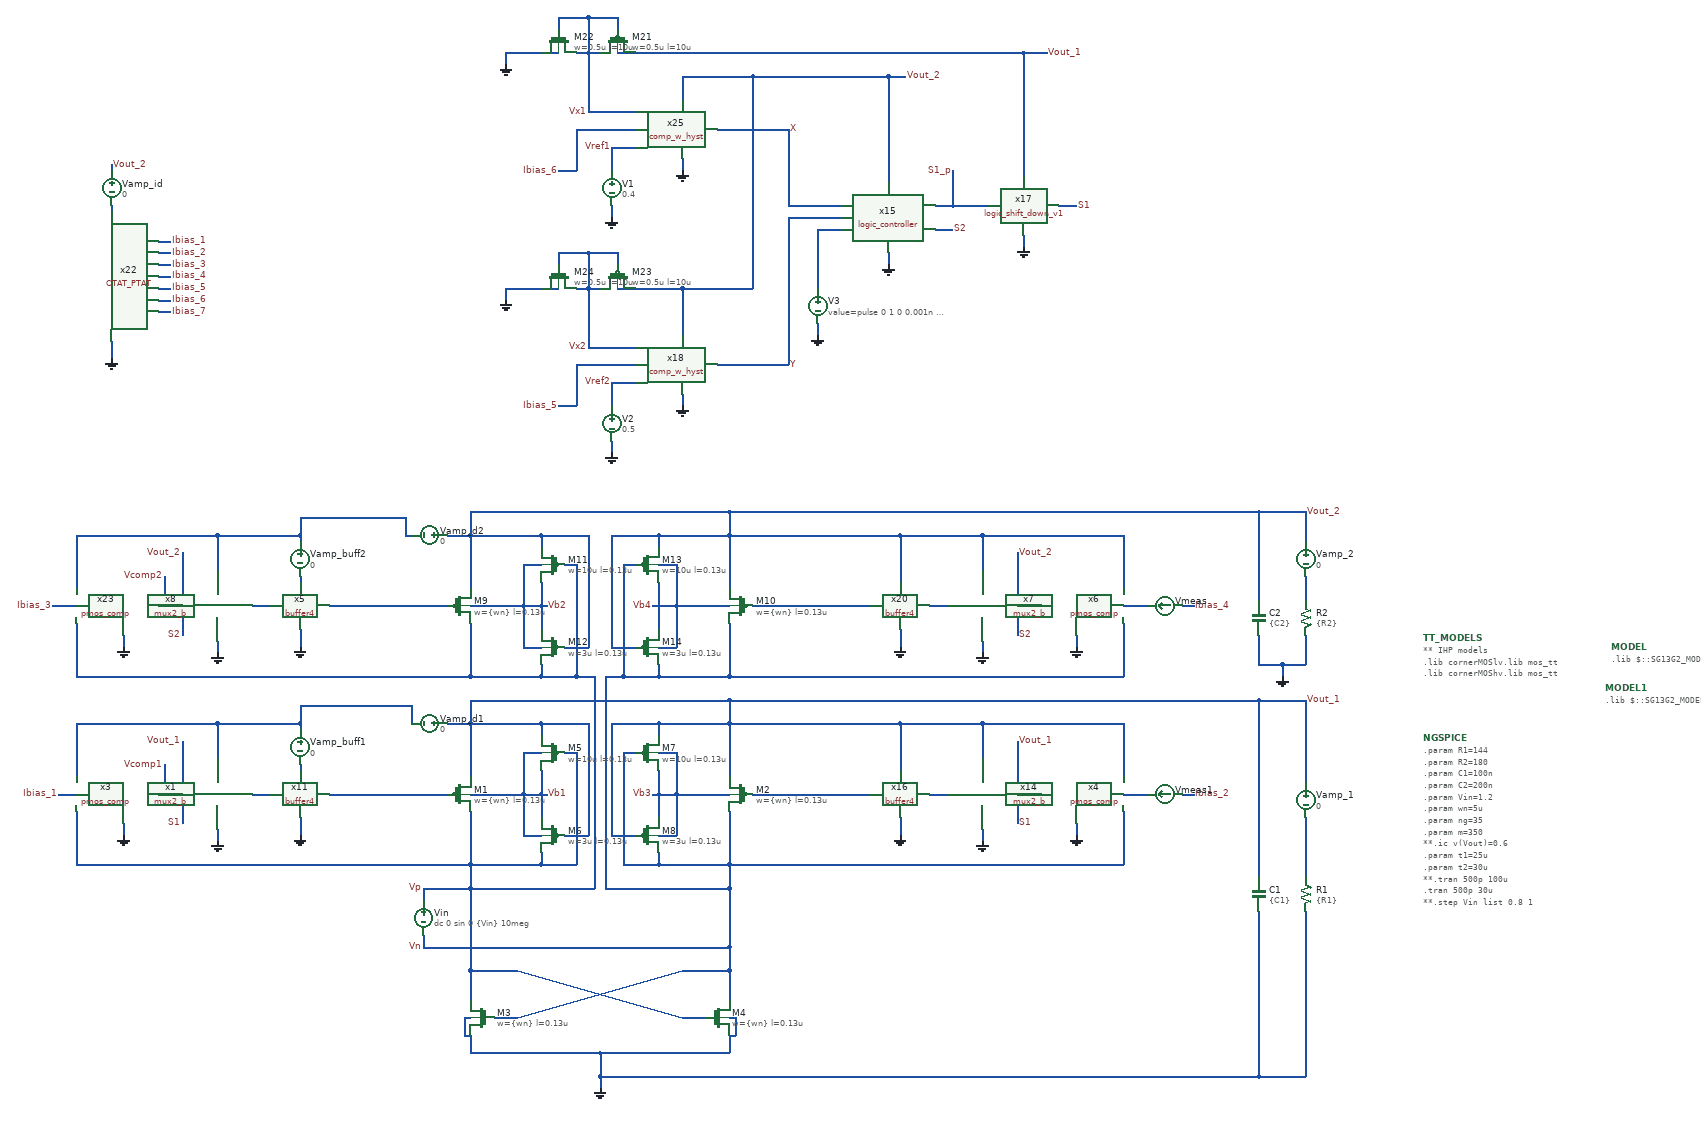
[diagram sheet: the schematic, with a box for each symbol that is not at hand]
v {xschem version=3.4.6 file_version=1.2}
G {}
K {}
V {}
S {}
E {}
P 4 1 1950 -490 {}
N 910 -700 930 -700 {lab=Vp}
N 910 -560 950 -560 {lab=Vout_1}
N 1010 -700 1030 -700 {lab=Vn}
N 990 -560 1030 -560 {lab=Vout_1}
N 1070 -630 1070 -590 {lab=Vb3}
N 1070 -670 1070 -630 {lab=Vb3}
N 870 -630 870 -590 {lab=Vb1}
N 840 -630 870 -630 {lab=Vb1}
N 870 -670 870 -630 {lab=Vb1}
N 930 -700 930 -510 {lab=Vp}
N 870 -510 930 -510 {lab=Vp}
N 750 -600 750 -510 {lab=Vp}
N 1190 -600 1190 -510 {lab=Vn}
N 1010 -700 1010 -510 {lab=Vn}
N 1070 -510 1190 -510 {lab=Vn}
N 990 -750 990 -560 {lab=Vout_1}
N 1070 -750 1190 -750 {lab=Vout_1}
N 950 -750 950 -560 {lab=Vout_1}
N 970 -190 1190 -190 {lab=GND}
N 1190 -330 1190 -280 {lab=Vn}
N 750 -330 750 -280 {lab=Vp}
N 790 -250 830 -250 {lab=Vn}
N 1110 -250 1150 -250 {lab=Vp}
N 830 -250 1110 -330 {lab=Vn}
N 830 -330 1110 -250 {lab=Vp}
N 750 -330 830 -330 {lab=Vp}
N 750 -470 750 -330 {lab=Vp}
N 1110 -330 1190 -330 {lab=Vn}
N 1190 -370 1190 -330 {lab=Vn}
N 670 -390 670 -370 {lab=Vn}
N 670 -370 1190 -370 {lab=Vn}
N 1190 -470 1190 -370 {lab=Vn}
N 670 -470 670 -450 {lab=Vp}
N 670 -470 750 -470 {lab=Vp}
N 750 -510 750 -470 {lab=Vp}
N 840 -700 870 -700 {lab=Vb1}
N 840 -700 840 -630 {lab=Vb1}
N 840 -560 870 -560 {lab=Vb1}
N 840 -630 840 -560 {lab=Vb1}
N 1070 -700 1100 -700 {lab=Vb3}
N 1100 -700 1100 -630 {lab=Vb3}
N 1070 -630 1100 -630 {lab=Vb3}
N 1070 -560 1100 -560 {lab=Vb3}
N 1100 -630 1100 -560 {lab=Vb3}
N 80 -600 80 -510 {lab=Vp}
N 80 -750 80 -660 {lab=#net1}
N 750 -790 750 -750 {lab=Vout_1}
N 750 -790 1190 -790 {lab=Vout_1}
N 1190 -790 1190 -750 {lab=Vout_1}
N 970 -150 970 -130 {lab=GND}
N 750 -190 970 -190 {lab=GND}
N 2090 -430 2090 -150 {lab=GND}
N 2170 -430 2170 -150 {lab=GND}
N 2090 -150 2170 -150 {lab=GND}
N 2090 -790 2090 -490 {lab=Vout_1}
N 2170 -590 2170 -490 {lab=#net2}
N 2170 -790 2170 -650 {lab=Vout_1}
N 1190 -250 1200 -250 {lab=GND}
N 1200 -250 1200 -220 {lab=GND}
N 1190 -220 1200 -220 {lab=GND}
N 1190 -220 1190 -190 {lab=GND}
N 750 -220 750 -190 {lab=GND}
N 740 -250 750 -250 {lab=GND}
N 740 -250 740 -220 {lab=GND}
N 740 -220 750 -220 {lab=GND}
N 510 -630 710 -630 {lab=#net3}
N 230 -680 230 -630 {lab=Vcomp1}
N 220 -630 230 -630 {lab=Vcomp1}
N 870 -630 880 -630 {lab=Vb1}
N 460 -590 460 -560 {lab=GND}
N 160 -580 160 -560 {lab=GND}
N 1860 -600 1860 -510 {lab=Vn}
N 1860 -750 1860 -660 {lab=Vout_1}
N 1480 -750 1480 -670 {lab=Vout_1}
N 1480 -590 1480 -560 {lab=GND}
N 1780 -580 1780 -560 {lab=GND}
N 1190 -510 1860 -510 {lab=Vn}
N 1190 -750 1480 -750 {lab=Vout_1}
N 1230 -630 1430 -630 {lab=#net4}
N 910 -1020 930 -1020 {lab=Vp}
N 910 -880 950 -880 {lab=Vout_2}
N 1010 -1020 1030 -1020 {lab=Vn}
N 990 -880 1030 -880 {lab=Vout_2}
N 1070 -950 1070 -910 {lab=Vb4}
N 1070 -990 1070 -950 {lab=Vb4}
N 870 -950 870 -910 {lab=Vb2}
N 840 -950 870 -950 {lab=Vb2}
N 870 -990 870 -950 {lab=Vb2}
N 870 -1070 950 -1070 {lab=Vout_2}
N 930 -1020 930 -830 {lab=Vp}
N 870 -830 930 -830 {lab=Vp}
N 750 -920 750 -830 {lab=Vp}
N 1190 -920 1190 -830 {lab=Vn}
N 1010 -1020 1010 -830 {lab=Vn}
N 1070 -830 1190 -830 {lab=Vn}
N 990 -1070 990 -880 {lab=Vout_2}
N 1070 -1070 1190 -1070 {lab=Vout_2}
N 950 -1070 950 -880 {lab=Vout_2}
N 840 -1020 870 -1020 {lab=Vb2}
N 840 -1020 840 -950 {lab=Vb2}
N 840 -880 870 -880 {lab=Vb2}
N 840 -950 840 -880 {lab=Vb2}
N 1070 -1020 1100 -1020 {lab=Vb4}
N 1100 -1020 1100 -950 {lab=Vb4}
N 1070 -950 1100 -950 {lab=Vb4}
N 1070 -880 1100 -880 {lab=Vb4}
N 1100 -950 1100 -880 {lab=Vb4}
N 80 -920 80 -830 {lab=Vp}
N 80 -1070 80 -980 {lab=#net5}
N 510 -950 710 -950 {lab=#net6}
N 230 -1000 230 -950 {lab=Vcomp2}
N 220 -950 230 -950 {lab=Vcomp2}
N 870 -950 880 -950 {lab=Vb2}
N 460 -910 460 -880 {lab=GND}
N 160 -900 160 -880 {lab=GND}
N 1860 -920 1860 -830 {lab=Vn}
N 1860 -1070 1860 -980 {lab=Vout_2}
N 1480 -1070 1480 -990 {lab=Vout_2}
N 1480 -910 1480 -880 {lab=GND}
N 1780 -900 1780 -880 {lab=GND}
N 1190 -830 1860 -830 {lab=Vn}
N 1190 -1070 1480 -1070 {lab=Vout_2}
N 1230 -950 1430 -950 {lab=#net7}
N 750 -470 960 -470 {lab=Vp}
N 930 -830 960 -830 {lab=Vp}
N 960 -830 960 -470 {lab=Vp}
N 980 -830 1010 -830 {lab=Vn}
N 980 -830 980 -470 {lab=Vn}
N 980 -470 1190 -470 {lab=Vn}
N 1190 -510 1190 -470 {lab=Vn}
N 2130 -850 2170 -850 {lab=GND}
N 2130 -850 2130 -830 {lab=GND}
N 2090 -850 2130 -850 {lab=GND}
N 970 -190 970 -150 {lab=GND}
N 2170 -900 2170 -850 {lab=GND}
N 2090 -900 2090 -850 {lab=GND}
N 2090 -1110 2090 -960 {lab=Vout_2}
N 2170 -1000 2170 -960 {lab=#net8}
N 2170 -1110 2170 -1060 {lab=Vout_2}
N 750 -1110 750 -1070 {lab=Vout_2}
N 1190 -1110 2090 -1110 {lab=Vout_2}
N 1190 -1110 1190 -1070 {lab=Vout_2}
N 750 -1110 1190 -1110 {lab=Vout_2}
N 50 -630 80 -630 {lab=Ibias_1}
N 1190 -790 2090 -790 {lab=Vout_1}
N 2090 -790 2170 -790 {lab=Vout_1}
N 2090 -1110 2170 -1110 {lab=Vout_2}
N 80 -510 750 -510 {lab=Vp}
N 1620 -1070 1860 -1070 {lab=Vout_2}
N 1620 -750 1860 -750 {lab=Vout_1}
N 80 -830 750 -830 {lab=Vp}
N 970 -150 2090 -150 {lab=GND}
N 230 -950 260 -950 {lab=Vcomp2}
N 230 -630 260 -630 {lab=Vcomp1}
N 140 -1400 140 -1370 {lab=GND}
N 1000 -1950 1000 -1930 {lab=Vx1}
N 900 -1950 950 -1950 {lab=Vx1}
N 900 -1950 900 -1930 {lab=Vx1}
N 930 -1890 950 -1890 {lab=Vx1}
N 950 -1950 950 -1890 {lab=Vx1}
N 950 -1950 1000 -1950 {lab=Vx1}
N 950 -1890 970 -1890 {lab=Vx1}
N 950 -1790 1030 -1790 {lab=Vx1}
N 950 -1890 950 -1790 {lab=Vx1}
N 990 -1730 990 -1690 {lab=Vref1}
N 990 -1730 1030 -1730 {lab=Vref1}
N 930 -1760 930 -1690 {lab=Ibias_6}
N 930 -1760 1030 -1760 {lab=Ibias_6}
N 990 -1630 990 -1610 {lab=GND}
N 810 -1890 810 -1870 {lab=GND}
N 810 -1890 900 -1890 {lab=GND}
N 1110 -1710 1110 -1690 {lab=GND}
N 1000 -1550 1000 -1530 {lab=Vx2}
N 900 -1550 950 -1550 {lab=Vx2}
N 900 -1550 900 -1530 {lab=Vx2}
N 930 -1490 950 -1490 {lab=Vx2}
N 950 -1550 950 -1490 {lab=Vx2}
N 950 -1550 1000 -1550 {lab=Vx2}
N 950 -1490 970 -1490 {lab=Vx2}
N 950 -1390 1030 -1390 {lab=Vx2}
N 950 -1490 950 -1390 {lab=Vx2}
N 990 -1330 990 -1290 {lab=Vref2}
N 990 -1330 1030 -1330 {lab=Vref2}
N 930 -1360 930 -1290 {lab=Ibias_5}
N 930 -1360 1030 -1360 {lab=Ibias_5}
N 990 -1230 990 -1210 {lab=GND}
N 810 -1490 810 -1470 {lab=GND}
N 810 -1490 900 -1490 {lab=GND}
N 1110 -1310 1110 -1290 {lab=GND}
N 1110 -1850 1110 -1810 {lab=Vout_2}
N 1460 -1550 1460 -1530 {lab=GND}
N 1290 -1630 1380 -1630 {lab=X}
N 1170 -1360 1290 -1360 {lab=Y}
N 1230 -1850 1230 -1490 {lab=Vout_2}
N 1170 -1760 1290 -1760 {lab=X}
N 1290 -1760 1290 -1630 {lab=X}
N 1290 -1610 1290 -1360 {lab=Y}
N 1290 -1610 1380 -1610 {lab=Y}
N 1460 -1850 1490 -1850 {lab=Vout_2}
N 1540 -1590 1570 -1590 {lab=S2}
N 1570 -1630 1630 -1630 {lab=S1_p}
N 1690 -1890 1690 -1680 {lab=Vout_1}
N 1690 -1890 1730 -1890 {lab=Vout_1}
N 1690 -1580 1690 -1560 {lab=GND}
N 1750 -1630 1780 -1630 {lab=S1}
N 380 -630 410 -630 {lab=#net9}
N 320 -570 320 -550 {lab=GND}
N 320 -750 320 -690 {lab=#net1}
N 80 -750 320 -750 {lab=#net1}
N 260 -610 260 -580 {lab=S1}
N 260 -720 260 -650 {lab=Vout_1}
N 1680 -630 1720 -630 {lab=#net10}
N 1530 -630 1560 -630 {lab=#net11}
N 1620 -570 1620 -550 {lab=GND}
N 1620 -750 1620 -690 {lab=Vout_1}
N 1680 -610 1680 -580 {lab=S1}
N 1680 -720 1680 -650 {lab=Vout_1}
N 1480 -750 1620 -750 {lab=Vout_1}
N 380 -950 410 -950 {lab=#net12}
N 320 -890 320 -870 {lab=GND}
N 320 -1070 320 -1010 {lab=#net5}
N 260 -930 260 -900 {lab=S2}
N 260 -1040 260 -970 {lab=Vout_2}
N 80 -1070 320 -1070 {lab=#net5}
N 1680 -950 1720 -950 {lab=#net13}
N 1530 -950 1560 -950 {lab=#net14}
N 1620 -890 1620 -870 {lab=GND}
N 1620 -1070 1620 -1010 {lab=Vout_2}
N 1680 -930 1680 -900 {lab=S2}
N 1680 -1040 1680 -970 {lab=Vout_2}
N 1480 -1070 1620 -1070 {lab=Vout_2}
N 1110 -1490 1230 -1490 {lab=Vout_2}
N 1000 -1890 1690 -1890 {lab=Vout_1}
N 1570 -1690 1570 -1630 {lab=S1_p}
N 1540 -1630 1570 -1630 {lab=S1_p}
N 1340 -1590 1380 -1590 {lab=#net15}
N 1860 -630 1900 -630 {lab=#net16}
N 1860 -950 1900 -950 {lab=#net17}
N 40 -950 80 -950 {lab=Ibias_3}
N 220 -1570 240 -1570 {lab=Ibias_1}
N 220 -1550 240 -1550 {lab=Ibias_2}
N 220 -1530 240 -1530 {lab=Ibias_3}
N 220 -1510 240 -1510 {lab=Ibias_4}
N 220 -1490 240 -1490 {lab=Ibias_5}
N 220 -1470 240 -1470 {lab=Ibias_6}
N 220 -1450 240 -1450 {lab=Ibias_7}
N 900 -1290 930 -1290 {lab=Ibias_5}
N 900 -1690 930 -1690 {lab=Ibias_6}
N 710 -1070 750 -1070 {lab=Vout_2}
N 710 -750 750 -750 {lab=Vout_1}
N 460 -1070 460 -1060 {lab=#net5}
N 320 -1070 460 -1070 {lab=#net5}
N 460 -1000 460 -990 {lab=#net18}
N 460 -680 460 -670 {lab=#net19}
N 460 -750 460 -740 {lab=#net1}
N 320 -750 460 -750 {lab=#net1}
N 640 -1070 650 -1070 {lab=#net5}
N 640 -1100 640 -1070 {lab=#net5}
N 460 -1100 460 -1070 {lab=#net5}
N 460 -1100 640 -1100 {lab=#net5}
N 650 -780 650 -750 {lab=#net1}
N 460 -780 460 -750 {lab=#net1}
N 460 -780 650 -780 {lab=#net1}
N 140 -1630 140 -1620 {lab=#net20}
N 140 -1700 140 -1690 {lab=Vout_2}
N 1960 -950 1980 -950 {lab=Ibias_4}
N 1960 -630 1980 -630 {lab=Ibias_2}
N 1060 -950 1070 -950 {lab=Vb4}
N 1060 -630 1070 -630 {lab=Vb3}
N 1110 -1490 1110 -1410 {lab=Vout_2}
N 1000 -1490 1110 -1490 {lab=Vout_2}
N 1110 -1850 1230 -1850 {lab=Vout_2}
N 1460 -1850 1460 -1670 {lab=Vout_2}
N 1230 -1850 1460 -1850 {lab=Vout_2}
N 870 -750 950 -750 {lab=Vout_1}
N 870 -1070 870 -1050 {lab=Vout_2}
N 750 -1070 870 -1070 {lab=Vout_2}
N 1070 -1070 1070 -1050 {lab=Vout_2}
N 990 -1070 1070 -1070 {lab=Vout_2}
N 870 -850 870 -830 {lab=Vp}
N 750 -830 870 -830 {lab=Vp}
N 750 -1070 750 -980 {lab=Vout_2}
N 750 -950 840 -950 {lab=Vb2}
N 1190 -1070 1190 -980 {lab=Vout_2}
N 1100 -950 1190 -950 {lab=Vb4}
N 1190 -750 1190 -660 {lab=Vout_1}
N 1100 -630 1190 -630 {lab=Vb3}
N 750 -750 750 -660 {lab=Vout_1}
N 750 -630 840 -630 {lab=Vb1}
N 870 -750 870 -730 {lab=Vout_1}
N 750 -750 870 -750 {lab=Vout_1}
N 1070 -750 1070 -730 {lab=Vout_1}
N 990 -750 1070 -750 {lab=Vout_1}
N 870 -530 870 -510 {lab=Vp}
N 750 -510 870 -510 {lab=Vp}
N 1070 -530 1070 -510 {lab=Vn}
N 1010 -510 1070 -510 {lab=Vn}
N 1070 -850 1070 -830 {lab=Vn}
N 1010 -830 1070 -830 {lab=Vn}
N 1340 -1430 1340 -1410 {lab=GND}
N 1340 -1590 1340 -1490 {lab=#net15}
C {sg13g2_pr/sg13_lv_pmos.sym} 730 -630 0 0 {name=M1
l=0.13u
w=\{wn\}
ng=\{ng\}
m=\{5*m\}
model=sg13_lv_pmos
spiceprefix=X
}
C {sg13g2_pr/sg13_lv_pmos.sym} 1210 -630 0 1 {name=M2
l=0.13u
w=\{wn\}
ng=\{ng\}
m=\{5*m\}
model=sg13_lv_pmos
spiceprefix=X
}
C {sg13g2_pr/sg13_lv_nmos.sym} 770 -250 0 1 {name=M3
l=0.13u
w=\{wn\}
ng=\{ng\}
m=\{3*m\}
model=sg13_lv_nmos
spiceprefix=X
}
C {sg13g2_pr/sg13_lv_nmos.sym} 1170 -250 0 0 {name=M4
l=0.13u
w=\{wn\}
ng=\{ng\}
m=\{3*m\}
model=sg13_lv_nmos
spiceprefix=X
}
C {sg13g2_pr/sg13_lv_pmos.sym} 890 -700 0 1 {name=M5
l=0.13u
w=10u
ng=1
m=1
model=sg13_lv_pmos
spiceprefix=X
}
C {sg13g2_pr/sg13_lv_pmos.sym} 890 -560 2 0 {name=M6
l=0.13u
w=3u
ng=1
m=1
model=sg13_lv_pmos
spiceprefix=X
}
C {sg13g2_pr/sg13_lv_pmos.sym} 1050 -700 0 0 {name=M7
l=0.13u
w=10u
ng=1
m=1
model=sg13_lv_pmos
spiceprefix=X
}
C {sg13g2_pr/sg13_lv_pmos.sym} 1050 -560 2 1 {name=M8
l=0.13u
w=3u
ng=1
m=1
model=sg13_lv_pmos
spiceprefix=X
}
C {vsource.sym} 670 -420 0 1 {name=Vin value="dc 0 sin 0 \{Vin\} 10meg" savecurrent=false}
C {lab_pin.sym} 670 -470 0 0 {name=p1 sig_type=std_logic lab=Vp}
C {lab_pin.sym} 670 -370 0 0 {name=p2 sig_type=std_logic lab=Vn}
C {gnd.sym} 140 -1370 0 0 {name=l1 lab=GND}
C {capa.sym} 2090 -460 0 0 {name=C1
m=1
value=\{C1\}
footprint=1206
device="ceramic capacitor"}
C {res.sym} 2170 -460 0 0 {name=R1
value=\{R1\}
footprint=1206
device=resistor
m=1}
C {vsource.sym} 2170 -620 0 0 {name=Vamp_1 value=0 savecurrent=false}
C {lab_pin.sym} 2170 -790 0 1 {name=p3 sig_type=std_logic lab=Vout_1}
C {gnd.sym} 970 -130 0 0 {name=l3 lab=GND}
C {lab_pin.sym} 230 -680 0 0 {name=p4 sig_type=std_logic lab=Vcomp1}
C {lab_pin.sym} 880 -630 0 1 {name=p6 sig_type=std_logic lab=Vb1}
C {gnd.sym} 160 -560 0 0 {name=l4 lab=GND}
C {gnd.sym} 460 -560 0 0 {name=l5 lab=GND}
C {code_shown.sym} 2370 -895 0 0 {
name=TT_MODELS
only_toplevel=true
value="
** IHP models
.lib cornerMOSlv.lib mos_tt
.lib cornerMOShv.lib mos_tt
"
spice_ignore=false
      }
C {code_shown.sym} 2370 -725 0 0 {name=NGSPICE
only_toplevel=false
value="
.param R1=144
.param R2=180
.param C1=100n
.param C2=200n
.param Vin=1.2
.param wn=5u
.param ng=35
.param m=350
**.ic v(Vout)=0.6
.param t1=25u
.param t2=30u
**.tran 500p 100u
.tran 500p 30u
**.step Vin list 0.8 1
.meas tran i_r1 AVG i(Vamp_1) from=t1 to=t2
.meas tran v_reg_1 AVG v(vout_1) from=t1 to=t2
.meas tran v_reg_2 AVG v(vout_2) from=t1 to=t2
.meas tran p_out_1 AVG par('((v(Vout_1)**2)/R1)') from=t1 to=t2
.meas tran p_out_2 AVG par('((v(Vout_2)**2)/R2)') from=t1 to=t2
.meas tran p_out AVG par('((v(Vout_1)**2)/R1)+((v(Vout_2)**2)/R2)') from=t1 to=t2
.meas tran p_in AVG par('-(v(Vp)-v(Vn))*i(Vin)') from=t1 to=t2
*.meas tran p_d1 AVG par('v(Vout_1)*(i(Vamp_gate1)+i(Vamp_buff1))*2') from=t1 to=t2
*.meas tran p_d2 AVG par('v(Vout_2)*(i(Vamp_gate2)+i(Vamp_buff2))*2') from=t1 to=t2
.meas tran p_id AVG par('v(Vout_2)*i(Vamp_id)') from=t1 to=t2
*.meas tran p_active_diodes param='(p_d1+p_d2)/p_in*100'
.meas tran p_id_percent param='p_id/p_in*100'
.meas tran i_driver1 AVG par('i(Vamp_d1)') from=t1 to=t2
.meas tran i_driver2 AVG par('i(Vamp_d2)') from=t1 to=t2
.meas tran PCE param='p_out/p_in' from=t1 to=t2
.meas tran VCR_1 param='v_reg_1/Vin'
.meas tran VCR_2 param='v_reg_2/Vin'
.save all
"}
C {gnd.sym} 1780 -560 0 1 {name=l6 lab=GND}
C {gnd.sym} 1480 -560 0 1 {name=l7 lab=GND}
C {sg13g2_pr/sg13_lv_pmos.sym} 730 -950 0 0 {name=M9
l=0.13u
w=\{wn\}
ng=\{ng\}
m=\{5*m\}
model=sg13_lv_pmos
spiceprefix=X
}
C {sg13g2_pr/sg13_lv_pmos.sym} 1210 -950 0 1 {name=M10
l=0.13u
w=\{wn\}
ng=\{ng\}
m=\{5*m\}
model=sg13_lv_pmos
spiceprefix=X
}
C {sg13g2_pr/sg13_lv_pmos.sym} 890 -1020 0 1 {name=M11
l=0.13u
w=10u
ng=1
m=1
model=sg13_lv_pmos
spiceprefix=X
}
C {sg13g2_pr/sg13_lv_pmos.sym} 890 -880 2 0 {name=M12
l=0.13u
w=3u
ng=1
m=1
model=sg13_lv_pmos
spiceprefix=X
}
C {sg13g2_pr/sg13_lv_pmos.sym} 1050 -1020 0 0 {name=M13
l=0.13u
w=10u
ng=1
m=1
model=sg13_lv_pmos
spiceprefix=X
}
C {sg13g2_pr/sg13_lv_pmos.sym} 1050 -880 2 1 {name=M14
l=0.13u
w=3u
ng=1
m=1
model=sg13_lv_pmos
spiceprefix=X
}
C {lab_pin.sym} 230 -1000 0 0 {name=p11 sig_type=std_logic lab=Vcomp2}
C {lab_pin.sym} 880 -950 0 1 {name=p14 sig_type=std_logic lab=Vb2}
C {gnd.sym} 160 -880 0 0 {name=l11 lab=GND}
C {gnd.sym} 460 -880 0 0 {name=l12 lab=GND}
C {gnd.sym} 1780 -880 0 1 {name=l14 lab=GND}
C {gnd.sym} 1480 -880 0 1 {name=l15 lab=GND}
C {capa.sym} 2090 -930 0 0 {name=C2
m=1
value=\{C2\}
footprint=1206
device="ceramic capacitor"}
C {res.sym} 2170 -930 0 0 {name=R2
value=\{R2\}
footprint=1206
device=resistor
m=1}
C {vsource.sym} 2170 -1030 0 0 {name=Vamp_2 value=0 savecurrent=false}
C {gnd.sym} 2130 -830 0 1 {name=l18 lab=GND}
C {lab_pin.sym} 2170 -1110 0 1 {name=p20 sig_type=std_logic lab=Vout_2}
C {sg13g2_pr/sg13_lv_pmos.sym} 1000 -1910 1 0 {name=M21
l=10u
w=0.5u
ng=1
m=19
model=sg13_lv_pmos
spiceprefix=X
}
C {sg13g2_pr/sg13_lv_nmos.sym} 900 -1910 1 0 {name=M22
l=10u
w=0.5u
ng=1
m=1
model=sg13_lv_nmos
spiceprefix=X
}
C {gnd.sym} 810 -1870 0 0 {name=l22 lab=GND}
C {vsource.sym} 990 -1660 0 0 {name=V1 value=0.4 savecurrent=false}
C {gnd.sym} 990 -1610 0 0 {name=l24 lab=GND}
C {gnd.sym} 1110 -1690 0 0 {name=l25 lab=GND}
C {sg13g2_pr/sg13_lv_pmos.sym} 1000 -1510 1 0 {name=M23
l=10u
w=0.5u
ng=1
m=10
model=sg13_lv_pmos
spiceprefix=X
}
C {sg13g2_pr/sg13_lv_nmos.sym} 900 -1510 1 0 {name=M24
l=10u
w=0.5u
ng=1
m=1
model=sg13_lv_nmos
spiceprefix=X
}
C {gnd.sym} 810 -1470 0 0 {name=l26 lab=GND}
C {vsource.sym} 990 -1260 0 0 {name=V2 value=0.5 savecurrent=false}
C {lab_pin.sym} 1730 -1890 0 1 {name=p27 sig_type=std_logic lab=Vout_1}
C {lab_pin.sym} 1490 -1850 0 1 {name=p28 sig_type=std_logic lab=Vout_2}
C {gnd.sym} 1460 -1530 0 0 {name=l30 lab=GND}
C {lab_pin.sym} 1570 -1590 0 1 {name=p26 sig_type=std_logic lab=S2}
C {gnd.sym} 1690 -1560 0 0 {name=l32 lab=GND}
C {lab_pin.sym} 1780 -1630 0 1 {name=p29 sig_type=std_logic lab=S1}
C {gnd.sym} 320 -550 0 0 {name=l33 lab=GND}
C {lab_pin.sym} 260 -720 0 0 {name=p30 sig_type=std_logic lab=Vout_1}
C {lab_pin.sym} 260 -580 0 0 {name=p31 sig_type=std_logic lab=S1}
C {gnd.sym} 1620 -550 0 1 {name=l34 lab=GND}
C {lab_pin.sym} 1680 -720 0 1 {name=p32 sig_type=std_logic lab=Vout_1}
C {lab_pin.sym} 1680 -580 0 1 {name=p33 sig_type=std_logic lab=S1}
C {gnd.sym} 320 -870 0 0 {name=l35 lab=GND}
C {lab_pin.sym} 260 -1040 0 0 {name=p34 sig_type=std_logic lab=Vout_2}
C {lab_pin.sym} 260 -900 0 0 {name=p35 sig_type=std_logic lab=S2}
C {gnd.sym} 1620 -870 0 1 {name=l36 lab=GND}
C {lab_pin.sym} 1680 -1040 0 1 {name=p36 sig_type=std_logic lab=Vout_2}
C {lab_pin.sym} 1680 -900 0 1 {name=p37 sig_type=std_logic lab=S2}
C {lab_pin.sym} 950 -1790 0 0 {name=p38 sig_type=std_logic lab=Vx1}
C {lab_pin.sym} 950 -1390 0 0 {name=p39 sig_type=std_logic lab=Vx2}
C {lab_pin.sym} 1290 -1360 0 1 {name=p41 sig_type=std_logic lab=Y}
C {lab_pin.sym} 1290 -1760 0 1 {name=p42 sig_type=std_logic lab=X}
C {lab_pin.sym} 990 -1730 0 0 {name=p43 sig_type=std_logic lab=Vref1}
C {lab_pin.sym} 990 -1330 0 0 {name=p44 sig_type=std_logic lab=Vref2}
C {lab_pin.sym} 1570 -1690 0 0 {name=p45 sig_type=std_logic lab=S1_p}
C {gnd.sym} 990 -1210 0 0 {name=l27 lab=GND}
C {gnd.sym} 1110 -1290 0 0 {name=l38 lab=GND}
C {lab_pin.sym} 140 -1700 0 1 {name=p49 sig_type=std_logic lab=Vout_2}
C {lab_pin.sym} 240 -1530 0 1 {name=p52 sig_type=std_logic lab=Ibias_3}
C {lab_pin.sym} 240 -1490 0 1 {name=p54 sig_type=std_logic lab=Ibias_5}
C {lab_pin.sym} 240 -1470 0 1 {name=p55 sig_type=std_logic lab=Ibias_6}
C {lab_pin.sym} 240 -1450 0 1 {name=p56 sig_type=std_logic lab=Ibias_7}
C {lab_pin.sym} 50 -630 0 0 {name=p57 sig_type=std_logic lab=Ibias_1}
C {lab_pin.sym} 1980 -630 0 1 {name=p58 sig_type=std_logic lab=Ibias_2}
C {lab_pin.sym} 1980 -950 0 1 {name=p59 sig_type=std_logic lab=Ibias_4}
C {lab_pin.sym} 40 -950 0 0 {name=p60 sig_type=std_logic lab=Ibias_3}
C {lab_pin.sym} 900 -1290 0 0 {name=p61 sig_type=std_logic lab=Ibias_5}
C {lab_pin.sym} 900 -1690 0 0 {name=p62 sig_type=std_logic lab=Ibias_6}
C {vsource.sym} 680 -1070 1 1 {name=Vamp_d2 value=0 savecurrent=false}
C {vsource.sym} 680 -750 1 1 {name=Vamp_d1 value=0 savecurrent=false}
C {vsource.sym} 460 -1030 0 1 {name=Vamp_buff2 value=0 savecurrent=false}
C {vsource.sym} 460 -710 0 1 {name=Vamp_buff1 value=0 savecurrent=false}
C {vsource.sym} 140 -1660 0 1 {name=Vamp_id value=0 savecurrent=false}
C {/shared/designs/SSDOR_1.2V_v2/components/comp_w_hyst/comp_w_hyst.sym} 1110 -1760 0 0 {name=x25}
C {/shared/designs/SSDOR_1.2V_v2/components/logic_contorller/logic_controller.sym} 1460 -1610 0 0 {name=x15}
C {/shared/designs/SSDOR_1.2V_v2/components/logic_shift_down_v1/logic_shift_down_v1.sym} 1690 -1630 0 0 {name=x17}
C {/shared/designs/SSDOR_1.2V_v2/components/comp_w_hyst/comp_w_hyst.sym} 1110 -1360 0 0 {name=x18}
C {/shared/designs/SSDOR_1.2V_v2/components/pmos_comp/pmos_comp.sym} 60 -880 0 0 {name=x23}
C {/shared/designs/SSDOR_1.2V_v2/components/pmos_comp/pmos_comp.sym} 60 -560 0 0 {name=x3}
C {/shared/designs/SSDOR_1.2V_v2/components/pmos_comp/pmos_comp.sym} 1880 -880 0 1 {name=x6}
C {/shared/designs/SSDOR_1.2V_v2/components/pmos_comp/pmos_comp.sym} 1880 -560 0 1 {name=x4}
C {/shared/designs/SSDOR_1.2V_v2/components/mux2_b/mux2_b.sym} 320 -950 0 0 {name=x8}
C {/shared/designs/SSDOR_1.2V_v2/components/mux2_b/mux2_b.sym} 320 -630 0 0 {name=x1}
C {/shared/designs/SSDOR_1.2V_v2/components/mux2_b/mux2_b.sym} 1620 -950 0 1 {name=x7}
C {/shared/designs/SSDOR_1.2V_v2/components/mux2_b/mux2_b.sym} 1620 -630 0 1 {name=x14}
C {ammeter.sym} 1930 -950 1 0 {name=Vmeas savecurrent=true spice_ignore=0}
C {ammeter.sym} 1930 -630 1 0 {name=Vmeas1 savecurrent=true spice_ignore=0}
C {devices/code_shown.sym} 2690 -880 0 0 {name=MODEL only_toplevel=true
format="tcleval( @value )"
value="
.lib $::SG13G2_MODELS/cornerRES.lib res_typ_stat
"}
C {lab_pin.sym} 240 -1510 0 1 {name=p68 sig_type=std_logic lab=Ibias_4}
C {lab_pin.sym} 240 -1570 0 1 {name=p53 sig_type=std_logic lab=Ibias_1}
C {lab_pin.sym} 240 -1550 0 1 {name=p70 sig_type=std_logic lab=Ibias_2}
C {/shared/designs/SSDOR_1.2V_v2/components/Ib_4u/CTAT_PTAT/CTAT_PTAT.sym} 140 -1510 0 0 {name=x22}
C {lab_pin.sym} 1060 -950 0 0 {name=p51 sig_type=std_logic lab=Vb4}
C {lab_pin.sym} 1060 -630 0 0 {name=p63 sig_type=std_logic lab=Vb3}
C {/shared/designs/SSDOR_1.2V_v2/components/buffer4/buffer4.sym} 390 -870 0 0 {name=x5 wn=5u}
C {/shared/designs/SSDOR_1.2V_v2/components/buffer4/buffer4.sym} 390 -550 0 0 {name=x11 wn=5u}
C {/shared/designs/SSDOR_1.2V_v2/components/buffer4/buffer4.sym} 1550 -550 0 1 {name=x16 wn=5u}
C {/shared/designs/SSDOR_1.2V_v2/components/buffer4/buffer4.sym} 1550 -870 0 1 {name=x20 wn=5u}
C {devices/code_shown.sym} 2680 -810 0 0 {name=MODEL1 only_toplevel=true
format="tcleval( @value )"
value="
.lib $::SG13G2_MODELS/cornerCAP.lib cap_wcs
"}
C {vsource.sym} 1340 -1460 0 0 {name=V3 value=value="pulse 0 1 0 0.001n 0.001n 0.3u 0.6u" savecurrent=false}
C {gnd.sym} 1340 -1410 0 0 {name=l2 lab=GND}
